VERSION 5.8 ;
BUSBITCHARS "[]" ;
DIVIDERCHAR "/" ;
UNITS
    DATABASE MICRONS 2000 ;
END UNITS

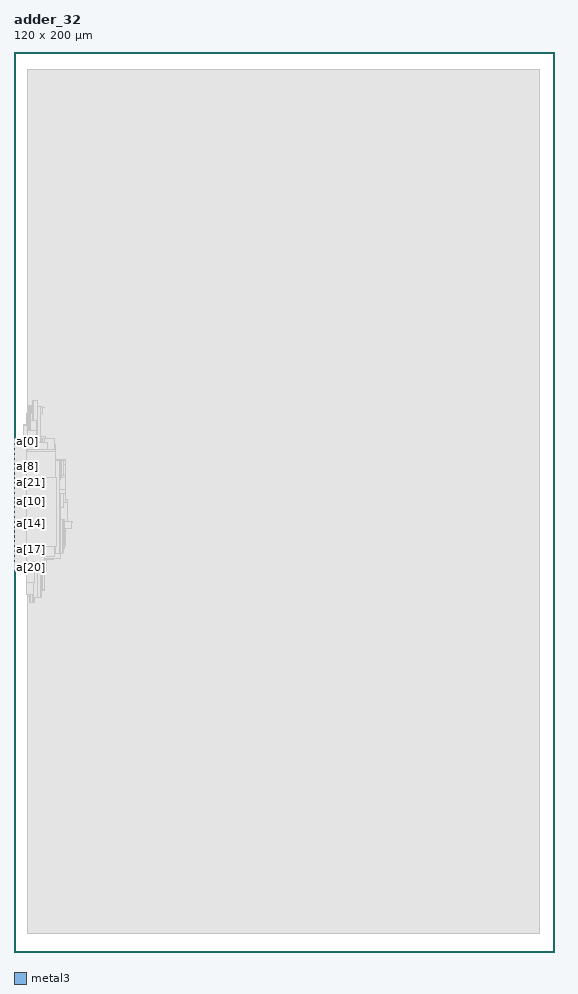
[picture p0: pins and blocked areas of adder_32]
MACRO adder_32
  FOREIGN adder_32 0 0 ;
  CLASS BLOCK ;
  SIZE 120 BY 200 ;
  PIN a[0]
    DIRECTION INPUT ;
    USE SIGNAL ;
    PORT
      LAYER metal3 ;
        RECT  0 113.435 0.07 113.505 ;
    END
  END a[0]
  PIN a[10]
    DIRECTION INPUT ;
    USE SIGNAL ;
    PORT
      LAYER metal3 ;
        RECT  0 99.995 0.07 100.065 ;
    END
  END a[10]
  PIN a[11]
    DIRECTION INPUT ;
    USE SIGNAL ;
    PORT
      LAYER metal3 ;
        RECT  0 100.275 0.07 100.345 ;
    END
  END a[11]
  PIN a[12]
    DIRECTION INPUT ;
    USE SIGNAL ;
    PORT
      LAYER metal3 ;
        RECT  0 99.715 0.07 99.785 ;
    END
  END a[12]
  PIN a[13]
    DIRECTION INPUT ;
    USE SIGNAL ;
    PORT
      LAYER metal3 ;
        RECT  0 91.595 0.07 91.665 ;
    END
  END a[13]
  PIN a[14]
    DIRECTION INPUT ;
    USE SIGNAL ;
    PORT
      LAYER metal3 ;
        RECT  0 96.915 0.07 96.985 ;
    END
  END a[14]
  PIN a[15]
    DIRECTION INPUT ;
    USE SIGNAL ;
    PORT
      LAYER metal3 ;
        RECT  0 101.115 0.07 101.185 ;
    END
  END a[15]
  PIN a[16]
    DIRECTION INPUT ;
    USE SIGNAL ;
    PORT
      LAYER metal3 ;
        RECT  0 99.435 0.07 99.505 ;
    END
  END a[16]
  PIN a[17]
    DIRECTION INPUT ;
    USE SIGNAL ;
    PORT
      LAYER metal3 ;
        RECT  0 89.355 0.07 89.425 ;
    END
  END a[17]
  PIN a[18]
    DIRECTION INPUT ;
    USE SIGNAL ;
    PORT
      LAYER metal3 ;
        RECT  0 92.715 0.07 92.785 ;
    END
  END a[18]
  PIN a[19]
    DIRECTION INPUT ;
    USE SIGNAL ;
    PORT
      LAYER metal3 ;
        RECT  0 101.955 0.07 102.025 ;
    END
  END a[19]
  PIN a[1]
    DIRECTION INPUT ;
    USE SIGNAL ;
    PORT
      LAYER metal3 ;
        RECT  0 99.155 0.07 99.225 ;
    END
  END a[1]
  PIN a[20]
    DIRECTION INPUT ;
    USE SIGNAL ;
    PORT
      LAYER metal3 ;
        RECT  0 87.115 0.07 87.185 ;
    END
  END a[20]
  PIN a[21]
    DIRECTION INPUT ;
    USE SIGNAL ;
    PORT
      LAYER metal3 ;
        RECT  0 102.515 0.07 102.585 ;
    END
  END a[21]
  PIN a[22]
    DIRECTION INPUT ;
    USE SIGNAL ;
    PORT
      LAYER metal3 ;
        RECT  0 92.435 0.07 92.505 ;
    END
  END a[22]
  PIN a[23]
    DIRECTION INPUT ;
    USE SIGNAL ;
    PORT
      LAYER metal3 ;
        RECT  0 98.875 0.07 98.945 ;
    END
  END a[23]
  PIN a[24]
    DIRECTION INPUT ;
    USE SIGNAL ;
    PORT
      LAYER metal3 ;
        RECT  0 92.155 0.07 92.225 ;
    END
  END a[24]
  PIN a[25]
    DIRECTION INPUT ;
    USE SIGNAL ;
    PORT
      LAYER metal3 ;
        RECT  0 100.555 0.07 100.625 ;
    END
  END a[25]
  PIN a[26]
    DIRECTION INPUT ;
    USE SIGNAL ;
    PORT
      LAYER metal3 ;
        RECT  0 89.075 0.07 89.145 ;
    END
  END a[26]
  PIN a[27]
    DIRECTION INPUT ;
    USE SIGNAL ;
    PORT
      LAYER metal3 ;
        RECT  0 87.675 0.07 87.745 ;
    END
  END a[27]
  PIN a[28]
    DIRECTION INPUT ;
    USE SIGNAL ;
    PORT
      LAYER metal3 ;
        RECT  0 103.915 0.07 103.985 ;
    END
  END a[28]
  PIN a[29]
    DIRECTION INPUT ;
    USE SIGNAL ;
    PORT
      LAYER metal3 ;
        RECT  0 104.195 0.07 104.265 ;
    END
  END a[29]
  PIN a[2]
    DIRECTION INPUT ;
    USE SIGNAL ;
    PORT
      LAYER metal3 ;
        RECT  0 104.475 0.07 104.545 ;
    END
  END a[2]
  PIN a[30]
    DIRECTION INPUT ;
    USE SIGNAL ;
    PORT
      LAYER metal3 ;
        RECT  0 98.315 0.07 98.385 ;
    END
  END a[30]
  PIN a[31]
    DIRECTION INPUT ;
    USE SIGNAL ;
    PORT
      LAYER metal3 ;
        RECT  0 91.875 0.07 91.945 ;
    END
  END a[31]
  PIN a[3]
    DIRECTION INPUT ;
    USE SIGNAL ;
    PORT
      LAYER metal3 ;
        RECT  0 105.035 0.07 105.105 ;
    END
  END a[3]
  PIN a[4]
    DIRECTION INPUT ;
    USE SIGNAL ;
    PORT
      LAYER metal3 ;
        RECT  0 105.315 0.07 105.385 ;
    END
  END a[4]
  PIN a[5]
    DIRECTION INPUT ;
    USE SIGNAL ;
    PORT
      LAYER metal3 ;
        RECT  0 98.035 0.07 98.105 ;
    END
  END a[5]
  PIN a[6]
    DIRECTION INPUT ;
    USE SIGNAL ;
    PORT
      LAYER metal3 ;
        RECT  0 96.355 0.07 96.425 ;
    END
  END a[6]
  PIN a[7]
    DIRECTION INPUT ;
    USE SIGNAL ;
    PORT
      LAYER metal3 ;
        RECT  0 88.795 0.07 88.865 ;
    END
  END a[7]
  PIN a[8]
    DIRECTION INPUT ;
    USE SIGNAL ;
    PORT
      LAYER metal3 ;
        RECT  0 106.155 0.07 106.225 ;
    END
  END a[8]
  PIN a[9]
    DIRECTION INPUT ;
    USE SIGNAL ;
    PORT
      LAYER metal3 ;
        RECT  0 97.755 0.07 97.825 ;
    END
  END a[9]
  PIN b[0]
    DIRECTION INPUT ;
    USE SIGNAL ;
    PORT
      LAYER metal3 ;
        RECT  0 106.435 0.07 106.505 ;
    END
  END b[0]
  PIN b[10]
    DIRECTION INPUT ;
    USE SIGNAL ;
    PORT
      LAYER metal3 ;
        RECT  0 106.715 0.07 106.785 ;
    END
  END b[10]
  PIN b[11]
    DIRECTION INPUT ;
    USE SIGNAL ;
    PORT
      LAYER metal3 ;
        RECT  0 91.315 0.07 91.385 ;
    END
  END b[11]
  PIN b[12]
    DIRECTION INPUT ;
    USE SIGNAL ;
    PORT
      LAYER metal3 ;
        RECT  0 97.475 0.07 97.545 ;
    END
  END b[12]
  PIN b[13]
    DIRECTION INPUT ;
    USE SIGNAL ;
    PORT
      LAYER metal3 ;
        RECT  0 107.275 0.07 107.345 ;
    END
  END b[13]
  PIN b[14]
    DIRECTION INPUT ;
    USE SIGNAL ;
    PORT
      LAYER metal3 ;
        RECT  0 107.555 0.07 107.625 ;
    END
  END b[14]
  PIN b[15]
    DIRECTION INPUT ;
    USE SIGNAL ;
    PORT
      LAYER metal3 ;
        RECT  0 90.755 0.07 90.825 ;
    END
  END b[15]
  PIN b[16]
    DIRECTION INPUT ;
    USE SIGNAL ;
    PORT
      LAYER metal3 ;
        RECT  0 91.035 0.07 91.105 ;
    END
  END b[16]
  PIN b[17]
    DIRECTION INPUT ;
    USE SIGNAL ;
    PORT
      LAYER metal3 ;
        RECT  0 108.115 0.07 108.185 ;
    END
  END b[17]
  PIN b[18]
    DIRECTION INPUT ;
    USE SIGNAL ;
    PORT
      LAYER metal3 ;
        RECT  0 103.635 0.07 103.705 ;
    END
  END b[18]
  PIN b[19]
    DIRECTION INPUT ;
    USE SIGNAL ;
    PORT
      LAYER metal3 ;
        RECT  0 108.675 0.07 108.745 ;
    END
  END b[19]
  PIN b[1]
    DIRECTION INPUT ;
    USE SIGNAL ;
    PORT
      LAYER metal3 ;
        RECT  0 88.515 0.07 88.585 ;
    END
  END b[1]
  PIN b[20]
    DIRECTION INPUT ;
    USE SIGNAL ;
    PORT
      LAYER metal3 ;
        RECT  0 108.955 0.07 109.025 ;
    END
  END b[20]
  PIN b[21]
    DIRECTION INPUT ;
    USE SIGNAL ;
    PORT
      LAYER metal3 ;
        RECT  0 101.395 0.07 101.465 ;
    END
  END b[21]
  PIN b[22]
    DIRECTION INPUT ;
    USE SIGNAL ;
    PORT
      LAYER metal3 ;
        RECT  0 109.515 0.07 109.585 ;
    END
  END b[22]
  PIN b[23]
    DIRECTION INPUT ;
    USE SIGNAL ;
    PORT
      LAYER metal3 ;
        RECT  0 96.635 0.07 96.705 ;
    END
  END b[23]
  PIN b[24]
    DIRECTION INPUT ;
    USE SIGNAL ;
    PORT
      LAYER metal3 ;
        RECT  0 109.795 0.07 109.865 ;
    END
  END b[24]
  PIN b[25]
    DIRECTION INPUT ;
    USE SIGNAL ;
    PORT
      LAYER metal3 ;
        RECT  0 106.995 0.07 107.065 ;
    END
  END b[25]
  PIN b[26]
    DIRECTION INPUT ;
    USE SIGNAL ;
    PORT
      LAYER metal3 ;
        RECT  0 110.075 0.07 110.145 ;
    END
  END b[26]
  PIN b[27]
    DIRECTION INPUT ;
    USE SIGNAL ;
    PORT
      LAYER metal3 ;
        RECT  0 87.395 0.07 87.465 ;
    END
  END b[27]
  PIN b[28]
    DIRECTION INPUT ;
    USE SIGNAL ;
    PORT
      LAYER metal3 ;
        RECT  0 105.875 0.07 105.945 ;
    END
  END b[28]
  PIN b[29]
    DIRECTION INPUT ;
    USE SIGNAL ;
    PORT
      LAYER metal3 ;
        RECT  0 103.075 0.07 103.145 ;
    END
  END b[29]
  PIN b[2]
    DIRECTION INPUT ;
    USE SIGNAL ;
    PORT
      LAYER metal3 ;
        RECT  0 104.755 0.07 104.825 ;
    END
  END b[2]
  PIN b[30]
    DIRECTION INPUT ;
    USE SIGNAL ;
    PORT
      LAYER metal3 ;
        RECT  0 96.075 0.07 96.145 ;
    END
  END b[30]
  PIN b[31]
    DIRECTION INPUT ;
    USE SIGNAL ;
    PORT
      LAYER metal3 ;
        RECT  0 110.635 0.07 110.705 ;
    END
  END b[31]
  PIN b[3]
    DIRECTION INPUT ;
    USE SIGNAL ;
    PORT
      LAYER metal3 ;
        RECT  0 110.915 0.07 110.985 ;
    END
  END b[3]
  PIN b[4]
    DIRECTION INPUT ;
    USE SIGNAL ;
    PORT
      LAYER metal3 ;
        RECT  0 102.795 0.07 102.865 ;
    END
  END b[4]
  PIN b[5]
    DIRECTION INPUT ;
    USE SIGNAL ;
    PORT
      LAYER metal3 ;
        RECT  0 95.795 0.07 95.865 ;
    END
  END b[5]
  PIN b[6]
    DIRECTION INPUT ;
    USE SIGNAL ;
    PORT
      LAYER metal3 ;
        RECT  0 97.195 0.07 97.265 ;
    END
  END b[6]
  PIN b[7]
    DIRECTION INPUT ;
    USE SIGNAL ;
    PORT
      LAYER metal3 ;
        RECT  0 101.675 0.07 101.745 ;
    END
  END b[7]
  PIN b[8]
    DIRECTION INPUT ;
    USE SIGNAL ;
    PORT
      LAYER metal3 ;
        RECT  0 111.475 0.07 111.545 ;
    END
  END b[8]
  PIN b[9]
    DIRECTION INPUT ;
    USE SIGNAL ;
    PORT
      LAYER metal3 ;
        RECT  0 95.515 0.07 95.585 ;
    END
  END b[9]
  PIN sum[0]
    DIRECTION OUTPUT ;
    USE SIGNAL ;
    PORT
      LAYER metal3 ;
        RECT  0 90.475 0.07 90.545 ;
    END
  END sum[0]
  PIN sum[10]
    DIRECTION OUTPUT ;
    USE SIGNAL ;
    PORT
      LAYER metal3 ;
        RECT  0 109.235 0.07 109.305 ;
    END
  END sum[10]
  PIN sum[11]
    DIRECTION OUTPUT ;
    USE SIGNAL ;
    PORT
      LAYER metal3 ;
        RECT  0 90.195 0.07 90.265 ;
    END
  END sum[11]
  PIN sum[12]
    DIRECTION OUTPUT ;
    USE SIGNAL ;
    PORT
      LAYER metal3 ;
        RECT  0 95.235 0.07 95.305 ;
    END
  END sum[12]
  PIN sum[13]
    DIRECTION OUTPUT ;
    USE SIGNAL ;
    PORT
      LAYER metal3 ;
        RECT  0 111.755 0.07 111.825 ;
    END
  END sum[13]
  PIN sum[14]
    DIRECTION OUTPUT ;
    USE SIGNAL ;
    PORT
      LAYER metal3 ;
        RECT  0 105.595 0.07 105.665 ;
    END
  END sum[14]
  PIN sum[15]
    DIRECTION OUTPUT ;
    USE SIGNAL ;
    PORT
      LAYER metal3 ;
        RECT  0 111.195 0.07 111.265 ;
    END
  END sum[15]
  PIN sum[16]
    DIRECTION OUTPUT ;
    USE SIGNAL ;
    PORT
      LAYER metal3 ;
        RECT  0 94.955 0.07 95.025 ;
    END
  END sum[16]
  PIN sum[17]
    DIRECTION OUTPUT ;
    USE SIGNAL ;
    PORT
      LAYER metal3 ;
        RECT  0 112.315 0.07 112.385 ;
    END
  END sum[17]
  PIN sum[18]
    DIRECTION OUTPUT ;
    USE SIGNAL ;
    PORT
      LAYER metal3 ;
        RECT  0 88.235 0.07 88.305 ;
    END
  END sum[18]
  PIN sum[19]
    DIRECTION OUTPUT ;
    USE SIGNAL ;
    PORT
      LAYER metal3 ;
        RECT  0 112.595 0.07 112.665 ;
    END
  END sum[19]
  PIN sum[1]
    DIRECTION OUTPUT ;
    USE SIGNAL ;
    PORT
      LAYER metal3 ;
        RECT  0 94.675 0.07 94.745 ;
    END
  END sum[1]
  PIN sum[20]
    DIRECTION OUTPUT ;
    USE SIGNAL ;
    PORT
      LAYER metal3 ;
        RECT  0 93.555 0.07 93.625 ;
    END
  END sum[20]
  PIN sum[21]
    DIRECTION OUTPUT ;
    USE SIGNAL ;
    PORT
      LAYER metal3 ;
        RECT  0 108.395 0.07 108.465 ;
    END
  END sum[21]
  PIN sum[22]
    DIRECTION OUTPUT ;
    USE SIGNAL ;
    PORT
      LAYER metal3 ;
        RECT  0 100.835 0.07 100.905 ;
    END
  END sum[22]
  PIN sum[23]
    DIRECTION OUTPUT ;
    USE SIGNAL ;
    PORT
      LAYER metal3 ;
        RECT  0 94.395 0.07 94.465 ;
    END
  END sum[23]
  PIN sum[24]
    DIRECTION OUTPUT ;
    USE SIGNAL ;
    PORT
      LAYER metal3 ;
        RECT  0 110.355 0.07 110.425 ;
    END
  END sum[24]
  PIN sum[25]
    DIRECTION OUTPUT ;
    USE SIGNAL ;
    PORT
      LAYER metal3 ;
        RECT  0 89.915 0.07 89.985 ;
    END
  END sum[25]
  PIN sum[26]
    DIRECTION OUTPUT ;
    USE SIGNAL ;
    PORT
      LAYER metal3 ;
        RECT  0 102.235 0.07 102.305 ;
    END
  END sum[26]
  PIN sum[27]
    DIRECTION OUTPUT ;
    USE SIGNAL ;
    PORT
      LAYER metal3 ;
        RECT  0 94.115 0.07 94.185 ;
    END
  END sum[27]
  PIN sum[28]
    DIRECTION OUTPUT ;
    USE SIGNAL ;
    PORT
      LAYER metal3 ;
        RECT  0 112.035 0.07 112.105 ;
    END
  END sum[28]
  PIN sum[29]
    DIRECTION OUTPUT ;
    USE SIGNAL ;
    PORT
      LAYER metal3 ;
        RECT  0 98.595 0.07 98.665 ;
    END
  END sum[29]
  PIN sum[2]
    DIRECTION OUTPUT ;
    USE SIGNAL ;
    PORT
      LAYER metal3 ;
        RECT  0 103.355 0.07 103.425 ;
    END
  END sum[2]
  PIN sum[30]
    DIRECTION OUTPUT ;
    USE SIGNAL ;
    PORT
      LAYER metal3 ;
        RECT  0 93.835 0.07 93.905 ;
    END
  END sum[30]
  PIN sum[31]
    DIRECTION OUTPUT ;
    USE SIGNAL ;
    PORT
      LAYER metal3 ;
        RECT  0 112.875 0.07 112.945 ;
    END
  END sum[31]
  PIN sum[3]
    DIRECTION OUTPUT ;
    USE SIGNAL ;
    PORT
      LAYER metal3 ;
        RECT  0 107.835 0.07 107.905 ;
    END
  END sum[3]
  PIN sum[4]
    DIRECTION OUTPUT ;
    USE SIGNAL ;
    PORT
      LAYER metal3 ;
        RECT  0 86.835 0.07 86.905 ;
    END
  END sum[4]
  PIN sum[5]
    DIRECTION OUTPUT ;
    USE SIGNAL ;
    PORT
      LAYER metal3 ;
        RECT  0 89.635 0.07 89.705 ;
    END
  END sum[5]
  PIN sum[6]
    DIRECTION OUTPUT ;
    USE SIGNAL ;
    PORT
      LAYER metal3 ;
        RECT  0 87.955 0.07 88.025 ;
    END
  END sum[6]
  PIN sum[7]
    DIRECTION OUTPUT ;
    USE SIGNAL ;
    PORT
      LAYER metal3 ;
        RECT  0 113.155 0.07 113.225 ;
    END
  END sum[7]
  PIN sum[8]
    DIRECTION OUTPUT ;
    USE SIGNAL ;
    PORT
      LAYER metal3 ;
        RECT  0 92.995 0.07 93.065 ;
    END
  END sum[8]
  PIN sum[9]
    DIRECTION OUTPUT ;
    USE SIGNAL ;
    PORT
      LAYER metal3 ;
        RECT  0 93.275 0.07 93.345 ;
    END
  END sum[9]
  OBS
    LAYER metal1 ;
     RECT  3.04 4.115 116.85 196.085 ;
    LAYER metal2 ;
     RECT  3.48 77.56 4.5 78.82 ;
     RECT  3.48 78.82 6.02 79.1 ;
     RECT  3.1 79.1 6.02 80.36 ;
     RECT  3.1 80.36 6.78 84.14 ;
     RECT  3.1 84.14 6.97 84.56 ;
     RECT  2.91 84.56 7.16 84.98 ;
     RECT  0.25 84.98 7.16 87.29 ;
     RECT  0.25 87.29 8.87 87.395 ;
     RECT  0.25 87.395 10.39 88.48 ;
     RECT  0.06 88.48 10.77 88.76 ;
     RECT  0.06 88.76 10.96 89.74 ;
     RECT  0.06 89.74 11.15 89.88 ;
     RECT  0.44 89.88 11.15 90.3 ;
     RECT  0.44 90.3 11.34 94.08 ;
     RECT  0.44 94.08 12.67 94.395 ;
     RECT  0.44 94.395 12.86 95.62 ;
     RECT  0.44 95.62 11.91 100.66 ;
     RECT  0.44 100.66 11.34 102.76 ;
     RECT  0.25 102.76 11.34 105.42 ;
     RECT  0.06 105.42 11.34 108.36 ;
     RECT  0.25 108.36 11.34 109.34 ;
     RECT  0.25 109.34 9.25 112.56 ;
     RECT  0.06 112.56 9.25 112.84 ;
     RECT  0.06 112.84 9.06 113.96 ;
     RECT  2.15 113.96 9.06 114.1 ;
     RECT  2.15 114.1 6.97 114.485 ;
     RECT  2.15 114.485 5.83 117.18 ;
     RECT  2.53 117.18 5.83 117.32 ;
     RECT  2.91 117.32 5.83 119.56 ;
     RECT  2.91 119.56 6.21 119.7 ;
     RECT  3.1 119.7 6.21 120.68 ;
     RECT  3.1 120.68 6.4 120.96 ;
     RECT  3.1 120.96 6.78 121.1 ;
     RECT  3.1 121.1 6.4 121.24 ;
     RECT  3.1 121.24 5.26 121.485 ;
     RECT  4.05 121.485 5.26 122.5 ;
    LAYER metal3 ;
     RECT  0.025 88.515 0.035 89.845 ;
     RECT  0.025 105.455 0.035 108.325 ;
     RECT  0.025 112.595 0.035 113.925 ;
     RECT  0.035 86.835 0.215 113.925 ;
     RECT  2.115 117.075 2.495 117.145 ;
     RECT  0.215 85.015 2.875 113.925 ;
     RECT  2.495 117.075 2.875 117.285 ;
     RECT  2.825 79.415 3.065 79.485 ;
     RECT  2.875 84.595 3.065 113.925 ;
     RECT  2.875 117.075 3.065 119.665 ;
     RECT  3.065 79.415 3.105 113.925 ;
     RECT  3.065 117.075 3.105 120.785 ;
     RECT  3.105 79.415 3.255 120.785 ;
     RECT  3.255 79.415 3.445 120.925 ;
     RECT  3.445 77.595 3.635 121.065 ;
     RECT  3.635 77.595 4.015 121.205 ;
     RECT  4.015 77.595 4.365 122.465 ;
     RECT  4.365 78.855 5.295 122.465 ;
     RECT  5.295 78.855 5.865 121.205 ;
     RECT  5.865 78.855 6.055 114.065 ;
     RECT  5.865 119.595 6.245 121.205 ;
     RECT  6.055 80.395 6.435 114.065 ;
     RECT  6.245 120.715 6.435 121.065 ;
     RECT  6.435 80.395 6.815 80.465 ;
     RECT  6.435 120.995 6.815 121.065 ;
     RECT  6.435 84.595 6.885 114.065 ;
     RECT  6.885 84.595 7.195 84.665 ;
     RECT  6.885 87.955 8.905 114.065 ;
     RECT  8.905 88.515 9.095 114.065 ;
     RECT  9.095 88.515 9.125 112.805 ;
     RECT  9.125 112.735 9.285 112.805 ;
     RECT  9.125 88.515 10.045 109.305 ;
     RECT  10.045 105.035 10.235 109.305 ;
     RECT  10.045 88.515 10.425 101.885 ;
     RECT  10.235 105.735 10.615 109.305 ;
     RECT  10.425 88.515 10.805 96.005 ;
     RECT  10.805 88.795 10.995 96.005 ;
     RECT  10.425 98.875 10.995 101.885 ;
     RECT  10.615 105.875 10.995 109.305 ;
     RECT  10.995 90.335 11.185 96.005 ;
     RECT  10.995 105.875 11.185 105.945 ;
     RECT  11.185 93.975 11.33 95.585 ;
     RECT  11.185 90.335 11.375 90.405 ;
     RECT  10.995 99.995 11.375 101.885 ;
     RECT  10.995 109.235 11.375 109.305 ;
     RECT  11.375 99.995 11.945 100.625 ;
     RECT  11.33 94.115 12.73 95.585 ;
     RECT  12.73 95.515 12.895 95.585 ;
    LAYER metal4 ;
     RECT  4.225 77.56 4.365 79.38 ;
     RECT  2.825 79.38 4.365 82.04 ;
     RECT  2.825 82.04 4.645 85.68 ;
     RECT  2.825 85.68 5.205 86.8 ;
     RECT  2.825 86.8 6.885 90.02 ;
     RECT  2.825 90.02 9.405 105.42 ;
     RECT  2.825 105.42 9.125 111.3 ;
     RECT  3.105 111.3 9.125 111.58 ;
     RECT  3.105 111.58 7.445 113.26 ;
     RECT  3.105 113.26 4.925 115.78 ;
     RECT  3.665 115.78 4.925 118.02 ;
     RECT  3.665 118.02 4.085 119.7 ;
     RECT  3.945 119.7 4.085 120.96 ;
    LAYER metal5 ;
     RECT  2.825 90.44 5.765 90.58 ;
  END
END adder_32
END LIBRARY
